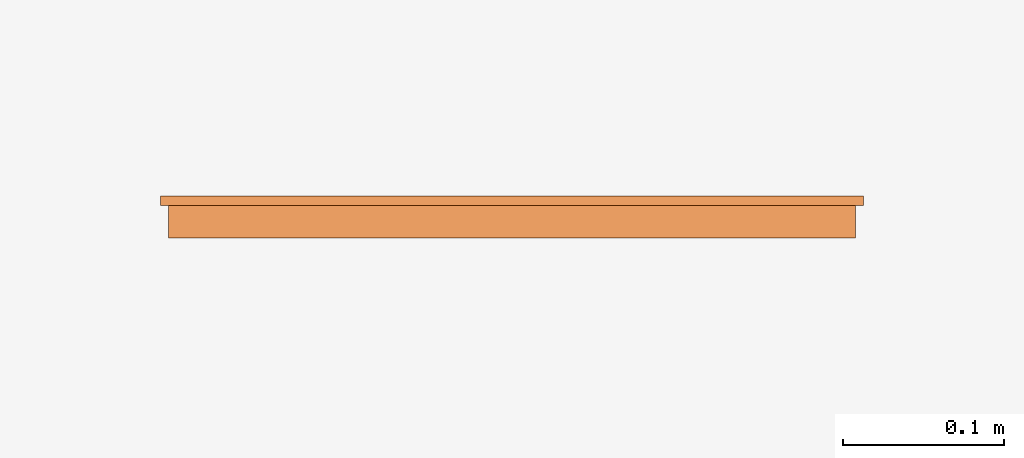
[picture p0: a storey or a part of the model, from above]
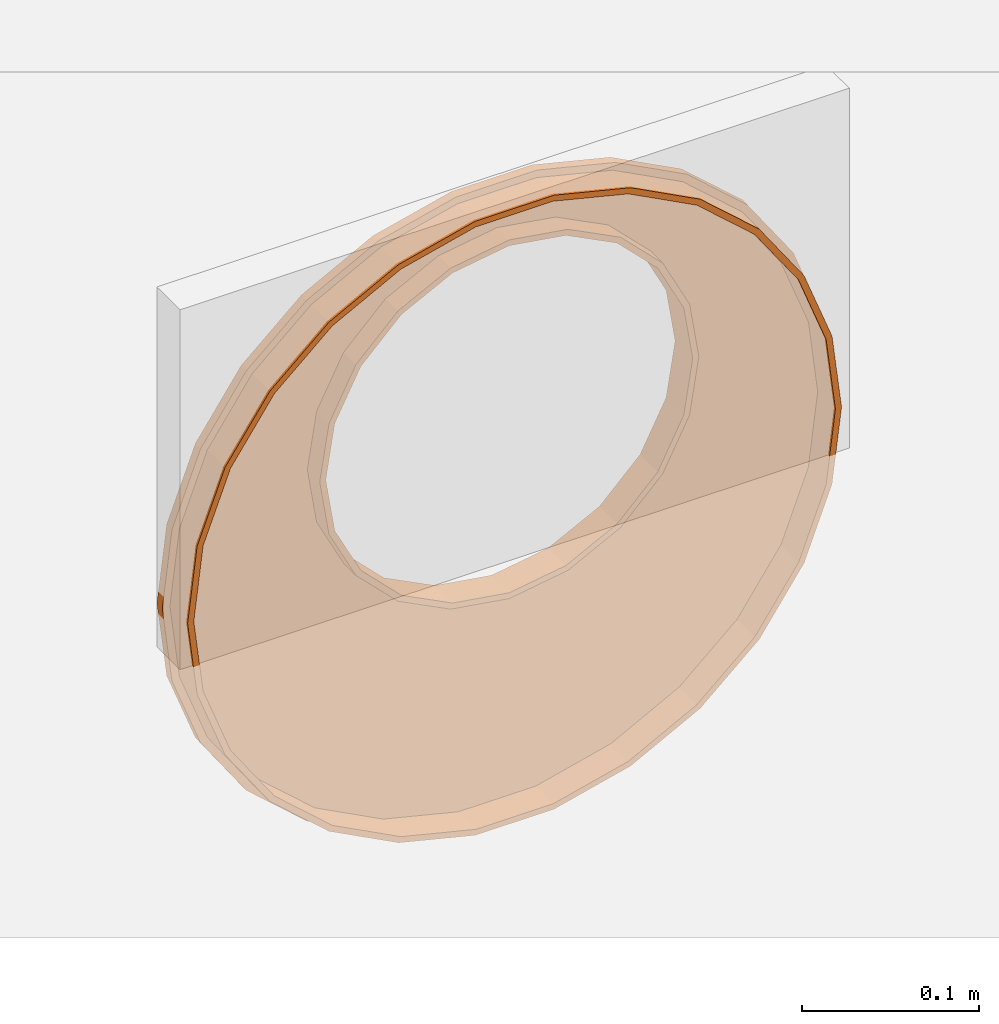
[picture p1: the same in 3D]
Properties of the parts of a building model (IFC2X3)

# File
Description: ViewDefinition [CoordinationView]
File name: 32880 - 225-350 Step Connector.ifc
Time: 2013-07-12T11:26:04
Written by: Autodesk Revit 2013
Made in: 20120221_2030(x64)

# IfcProject, Project Number
LongName: Project Name; Phase: Project Status

# IfcSite, Default
RefLatitude: 42, 21, 30, 344238; RefLongitude: -71, -3, -35, -194702; RefElevation: 0 mm

# IfcBuilding
Pset_BuildingCommon - NumberOfStoreys: 1
Other - Project Issue Date: Issue Date; Project Name: Project Name; Client Name: Owner; Project Number: Project Number; Project Address: ## Street City, State Zip; Project Status: Project Status

# IfcBuildingStorey, Level 1
LongName: Level 1; Elevation: 0 mm
Constraints - Elevation Base: 0; Elevation: 0 mm
Graphics - Color: 0; Symbol: M_Level Head - Circle: M_Level Head - Circle; Line Pattern: Center; Line Weight: 1; Symbol at End 1 Default: no; Symbol at End 2 Default: yes
Identity Data - Structural: no; Name: Level 1; Building Story: yes
Dimensions - Computation Height: 0 mm

# IfcBuildingElementProxy: 32880 - 225-350 Step Connector, 32880 - 225-350 Step Connector:32880 - 225-350 Step Connector:32880 - 225-350 Step Connector:563684
In: Level 1
Constraints - Moves With Nearby Elements: no; Level: Level: Level 1
Phasing - Phase Created: New Construction
Dimensions - Volume: 775473 mm3; Step Connector Depth: 370 mm
Pset_BuildingElementProxyCommon - Reference: 32880 - 225-350 Step Connector

# IfcOpeningElement: Recess
In: Level 1
Constraints - Height Offset From Level: 0 mm; Level: Level: Level 1; Related to Mass: no; Room Bounding: yes
Dimensions - Perimeter: 50000 mm; Thickness: 400 mm; Volume: 54033190656 mm3; Area: 135090000 mm2
Phasing - Phase Created: New Construction
Structural - Structural: no; Enable Analytical Model: no
Construction - Default Thickness: 400 mm; Function: 0
Materials and Finishes - Structural Material: Plant
Analytical Properties - Roughness: 1; Absorptance: 0.1
Graphics - Coarse Scale Fill Color: 0

# IfcSlab: Floor:Generic Floor - 400mm, Floor:Generic Floor - 400mm:193825
In: Level 1
PredefinedType: FLOOR; Material: Plant 400 mm
Constraints - Height Offset From Level: 0 mm; Level: Level: Level 1; Related to Mass: no; Room Bounding: yes
Dimensions - Perimeter: 50000 mm; Thickness: 400 mm; Volume: 54033190656 mm3; Area: 135090000 mm2
Phasing - Phase Created: New Construction
Structural - Structural: no; Enable Analytical Model: no
Pset_SlabCommon - Reference: Generic Floor - 400mm; IsExternal: no; LoadBearing: yes
Construction - Default Thickness: 400 mm; Function: 0
Materials and Finishes - Structural Material: Plant
Analytical Properties - Roughness: 1; Absorptance: 0.1
Graphics - Coarse Scale Fill Color: 0
